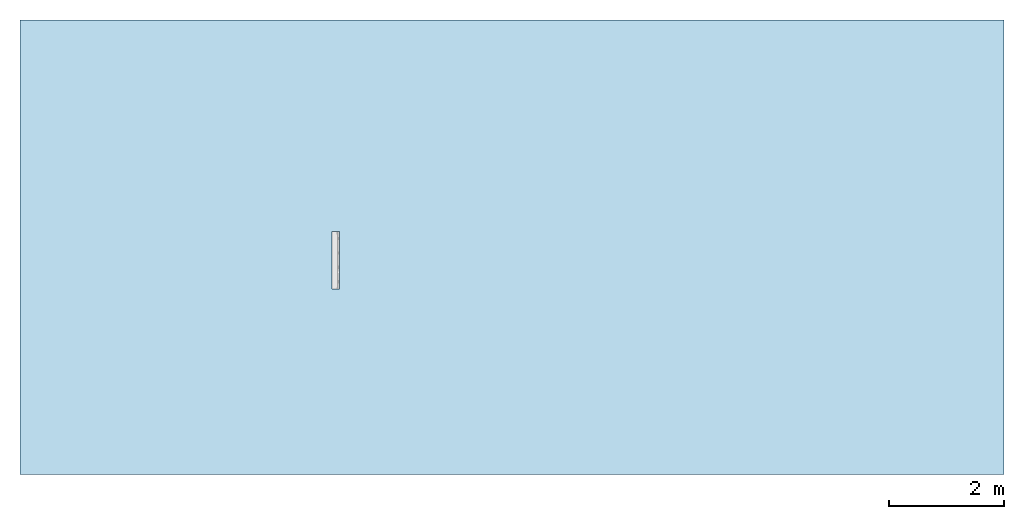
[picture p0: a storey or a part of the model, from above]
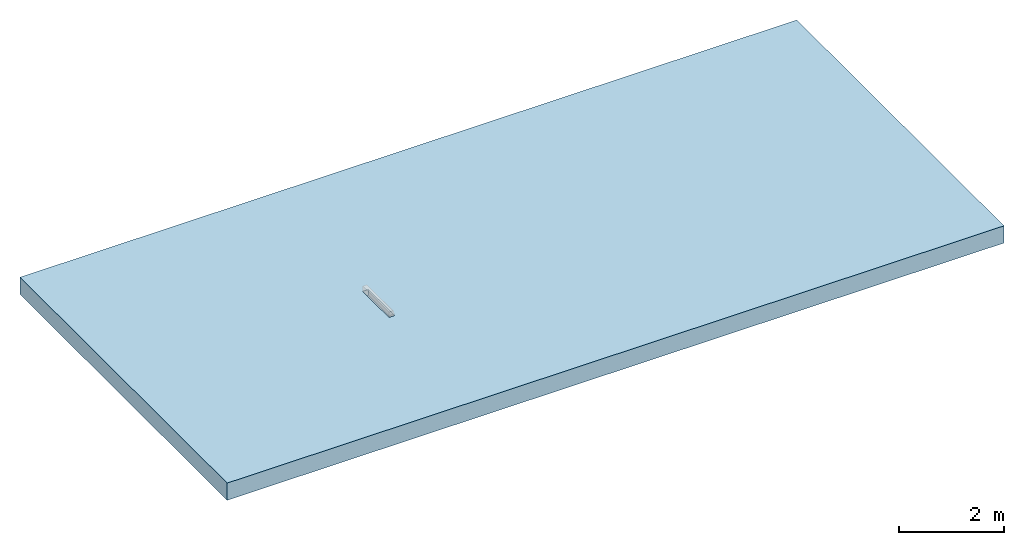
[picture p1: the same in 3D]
Properties of the parts of a building model (IFC2X3)

# File
Description: ViewDefinition [CoordinationView]
File name: 7950 - KDHB255 channel - 1000mm LG.ifc
Time: 2013-08-30T17:40:00
Written by: Autodesk Revit 2013
Made in: 20120221_2030(x64)

# IfcProject, Project Number
LongName: Project Name; Phase: Project Status

# IfcSite, Default
RefLatitude: 42, 21, 30, 344238; RefLongitude: -71, -3, -35, -194702; RefElevation: 0 mm

# IfcBuilding
Pset_BuildingCommon - NumberOfStoreys: 1
Other - Project Status: Project Status; Project Address: ## Street City, State Zip; Project Issue Date: Issue Date; Project Name: Project Name; Project Number: Project Number; Client Name: Owner

# IfcBuildingStorey, Level 1
LongName: Level 1; Elevation: 0 mm
Constraints - Elevation Base: 0; Elevation: 0 mm
Graphics - Symbol at End 2 Default: yes; Line Pattern: Center; Line Weight: 1; Color: 0; Symbol at End 1 Default: no; Symbol: M_Level Head - Circle: M_Level Head - Circle
Identity Data - Building Story: yes; Name: Level 1; Structural: no
Dimensions - Computation Height: 0 mm

# IfcBuildingElementProxy: 7950 - KDHB255 channel - 1000mm LG, Civil-Drainage-Channel-ACO-KerbDrain-HB255:7950 - KDHB255 channel - 1000mm LG:7950 - KDHB255 channel - 1000mm LG:754467
In: Level 1
Material: ACO Polymer Concrete.
Phasing - Phase Created: New Construction
Dimensions - Volume: 18985488 mm3; LH Void Start: -2000 mm; RH Void Start: -2000 mm; LH Void End: -2005 mm; Void Width: 125 mm; Void Start: 0 mm; RH Hole End: -2005 mm; Void Length: 1000 mm; Void Depth: -130 mm; Access Depth: 2000 mm
Constraints - Moves With Nearby Elements: no; Level: Level: Level 1
Pset_BuildingElementProxyCommon - Reference: 7950 - KDHB255 channel - 1000mm LG
Identity Data - Maintenance guidelines: http://www.aco.co.uk/download.php?id=120; Price: POA - contact ACO; URL: www.aco.co.uk; Model Description: Combined kerb and drainage system; Manufacturer: ACO Technologies plc - ACO Water Management Division; Product Code: 7950; e-mail Sales: customersupport@aco.co.uk; Fax: +44 (0)1462 815895; OmniClass Title: Rainwater Removal; Telephone: +44 (0)1462 816666; Cost: 0; Assembly Description: Rain Water Drainage; Installation guidelines: http://www.aco.co.uk/download.php?id=120; Address: ACO Business Park, Hitchin Road, Shefford, Bedfordshire, United Kingdom SG17 5TE; OmniClass Number: 23.70.50.24; Product Page URL: http://www.aco.co.uk/product_detail.php?id=3; Model: ACO KerbDrain HB255; Product brochure: http://www.aco.co.uk/download.php?id=120; Assembly Code: D2040; e-mail Technical: technical@aco.co.uk; Type Comments: ACO KerbDrain HB255 half battered kerb unit 1000mm long
Data - Invert Depth: 235mm; Product Dimensions: 1000mm x 125mm x 255mm (LxWxH); Hydraulic Performance: http://www.aco.co.uk/download.php?id=120; Drainage Slot Width: 50mm; Load Class: A 15 - D 400 A 15 - D 400; Connection Pipe O.D: N/A; Product Weight: 37.2 Kg; ACO Hydraulic Design Software: http://www.acodesign.co.uk; Concrete Surround Volume - Load Class A 15 - D 400 - Concrete Pavement: 0.12m³/m; Installation - Concrete Grade: Refer to brochure; Concrete Surround Volume - Load Class A 15 - D 400 - Grass or Asphalt Pavement: 0.11m³/m; Channel C.S.A: 0.01m²; Drainage Slot Intake area: 14592mm²/m; Product Standard: BS EN 1433:2002, CE marked, Kitemarked
General - SerialNumber: 0.000000; TagNumber: 0.000000
Construction - Closing end cap: no; LH drop kerb: no; Access Unit: no; HB255 - 500: no; HB255 - 1000: yes; Centre Stone: no; RH drop kerb: no
Materials and Finishes - End Cap Colour: N/A; Access Cover/Frame Finish: N/A; Access Cover/Frame Colour: N/A; Channel Colour: Grey; Channel Material: Vienite® Synthetic Resin Concrete; Access Cover/Frame Material: N/A; End Cap Material: N/A
Other - CreatedBy: www.aco.co.uk; Revision: 1
Green Building Properties - End Cap Recycled Material Content: N/A; End Cap Recyclable: N/A; Channel Recyclable: Fully recyclable; Access Cover/Frame Recyclable: N/A; Access Cover/Frame Recycled Material Content: N/A; Channel Recycled Material Content: 20% minimum

# IfcOpeningElement: Recess (3)
In: Level 1
Constraints - Related to Mass: no; Room Bounding: yes; Level: Level: Level 1; Height Offset From Level: 0 mm
Phasing - Phase Created: New Construction
Dimensions - Area: 135090000 mm2; Volume: 54019750000 mm3; Perimeter: 50000 mm; Thickness: 400 mm
Structural - Enable Analytical Model: no; Structural: no
Graphics - Coarse Scale Fill Color: 0
Materials and Finishes - Structural Material: Plant
Construction - Function: 0; Default Thickness: 400 mm
Analytical Properties - Absorptance: 0.1; Roughness: 1

# IfcSlab: Floor:Generic Floor - 400mm, Floor:Generic Floor - 400mm:193825
In: Level 1
PredefinedType: FLOOR; Material: Plant 400 mm
Constraints - Related to Mass: no; Room Bounding: yes; Level: Level: Level 1; Height Offset From Level: 0 mm
Phasing - Phase Created: New Construction
Dimensions - Area: 135090000 mm2; Volume: 54019750000 mm3; Perimeter: 50000 mm; Thickness: 400 mm
Structural - Enable Analytical Model: no; Structural: no
Pset_SlabCommon - Reference: Generic Floor - 400mm; IsExternal: no; LoadBearing: yes
Graphics - Coarse Scale Fill Color: 0
Materials and Finishes - Structural Material: Plant
Construction - Function: 0; Default Thickness: 400 mm
Analytical Properties - Absorptance: 0.1; Roughness: 1
